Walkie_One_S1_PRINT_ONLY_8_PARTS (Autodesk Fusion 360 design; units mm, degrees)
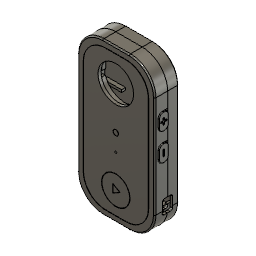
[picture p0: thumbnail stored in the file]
part number: 2026-09-16-19-15-10-916
part number: 2026-09-16-19-15-11-455
part number: 2026-09-16-19-15-11-502
part number: 2026-09-16-19-15-11-538
part number: 2026-09-16-19-15-11-567
part number: 2026-09-16-19-15-11-598
part number: 2026-09-16-19-15-11-628
part number: 2026-09-16-19-15-11-658
part number: 2026-09-16-19-15-11-693
base_feature "Base Feature1" bodies "01_Front_Shell"
base_feature "Base Feature1" bodies "02_Rear_Cover"
base_feature "Base Feature1" bodies "03_Talk"
base_feature "Base Feature1" bodies "04_Volume_Up"
base_feature "Base Feature1" bodies "05_Volume_Down"
base_feature "Base Feature1" bodies "06_Play"
base_feature "Base Feature1" bodies "07_Control_Bridge"
base_feature "Base Feature1" bodies "08_Light_Guide_CLEAR"
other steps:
create_component "CreateComponent1"
create_component "CreateComponent2"
create_component "CreateComponent3"
create_component "CreateComponent4"
create_component "CreateComponent5"
create_component "CreateComponent6"
create_component "CreateComponent7"
create_component "CreateComponent8"
named bodies: "01_Front_Shell", "02_Rear_Cover", "03_Talk", "04_Volume_Up", "05_Volume_Down", "06_Play", "07_Control_Bridge", "08_Light_Guide_CLEAR"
